# ICPS2023_5_fd_base -- LEF macro views (generated from the GDS)
# Layer names follow the PDK design layers (see libs.tech/klayout/doc/layers.md).
# Geometry is metal-only pad ring hardware; no LEF tech file is shipped yet
# (that arrives with the LibreLane/OpenROAD bring-up).
VERSION 5.7 ;
BUSBITCHARS "[]" ;
DIVIDERCHAR "/" ;
UNITS
  DATABASE MICRONS 1000 ;   # PDK database unit is 0.001 um
END UNITS
MANUFACTURINGGRID 0.001 ;

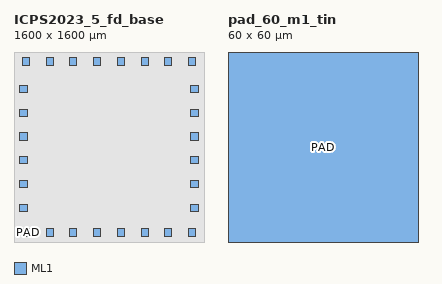
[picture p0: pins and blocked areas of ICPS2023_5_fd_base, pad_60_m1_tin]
MACRO ICPS2023_5_fd_base
  CLASS BLOCK ;
  ORIGIN 0 0 ;
  FOREIGN ICPS2023_5_fd_base 0 0 ;
  SIZE 1600.0 BY 1600.0 ;
  SYMMETRY X Y ;
  PIN PAD
    DIRECTION INOUT ;
    USE ANALOG ;
    PORT
      LAYER ML1 ;
      RECT 70.0 50.0 130.0 110.0 ;
      RECT 270.0 50.0 330.0 110.0 ;
      RECT 470.0 50.0 530.0 110.0 ;
      RECT 670.0 50.0 730.0 110.0 ;
      RECT 870.0 50.0 930.0 110.0 ;
      RECT 1070.0 50.0 1130.0 110.0 ;
      RECT 1270.0 50.0 1330.0 110.0 ;
      RECT 1470.0 50.0 1530.0 110.0 ;
      RECT 50.0 258.0 110.0 318.0 ;
      RECT 1490.0 258.0 1550.0 318.0 ;
      RECT 50.0 458.0 110.0 518.0 ;
      RECT 1490.0 458.0 1550.0 518.0 ;
      RECT 50.0 658.0 110.0 718.0 ;
      RECT 1490.0 658.0 1550.0 718.0 ;
      RECT 50.0 858.0 110.0 918.0 ;
      RECT 1490.0 858.0 1550.0 918.0 ;
      RECT 50.0 1058.0 110.0 1118.0 ;
      RECT 1490.0 1058.0 1550.0 1118.0 ;
      RECT 50.0 1258.0 110.0 1318.0 ;
      RECT 1490.0 1258.0 1550.0 1318.0 ;
      RECT 70.0 1490.0 130.0 1550.0 ;
      RECT 270.0 1490.0 330.0 1550.0 ;
      RECT 470.0 1490.0 530.0 1550.0 ;
      RECT 670.0 1490.0 730.0 1550.0 ;
      RECT 870.0 1490.0 930.0 1550.0 ;
      RECT 1070.0 1490.0 1130.0 1550.0 ;
      RECT 1270.0 1490.0 1330.0 1550.0 ;
      RECT 1470.0 1490.0 1530.0 1550.0 ;
    END
  END PAD
  OBS
    LAYER CNT ;
      RECT 1495.0 1264.0 1500.0 1269.0 ;
      RECT 1510.0 1264.0 1515.0 1269.0 ;
      RECT 1525.0 1264.0 1530.0 1269.0 ;
      RECT 1540.0 1264.0 1545.0 1269.0 ;
      RECT 1495.0 1279.0 1500.0 1284.0 ;
      RECT 1510.0 1279.0 1515.0 1284.0 ;
      RECT 1525.0 1279.0 1530.0 1284.0 ;
      RECT 1540.0 1279.0 1545.0 1284.0 ;
      RECT 1495.0 1294.0 1500.0 1299.0 ;
      RECT 1510.0 1294.0 1515.0 1299.0 ;
      RECT 1525.0 1294.0 1530.0 1299.0 ;
      RECT 1540.0 1294.0 1545.0 1299.0 ;
      RECT 1495.0 1309.0 1500.0 1314.0 ;
      RECT 1510.0 1309.0 1515.0 1314.0 ;
      RECT 1525.0 1309.0 1530.0 1314.0 ;
      RECT 1540.0 1309.0 1545.0 1314.0 ;
      RECT 1276.0 1495.0 1281.0 1500.0 ;
      RECT 1291.0 1495.0 1296.0 1500.0 ;
      RECT 1306.0 1495.0 1311.0 1500.0 ;
      RECT 1321.0 1495.0 1326.0 1500.0 ;
      RECT 1476.0 1495.0 1481.0 1500.0 ;
      RECT 1491.0 1495.0 1496.0 1500.0 ;
      RECT 1506.0 1495.0 1511.0 1500.0 ;
      RECT 1521.0 1495.0 1526.0 1500.0 ;
      RECT 1276.0 1510.0 1281.0 1515.0 ;
      RECT 1291.0 1510.0 1296.0 1515.0 ;
      RECT 1306.0 1510.0 1311.0 1515.0 ;
      RECT 1321.0 1510.0 1326.0 1515.0 ;
      RECT 1476.0 1510.0 1481.0 1515.0 ;
      RECT 1491.0 1510.0 1496.0 1515.0 ;
      RECT 1506.0 1510.0 1511.0 1515.0 ;
      RECT 1521.0 1510.0 1526.0 1515.0 ;
      RECT 1276.0 1525.0 1281.0 1530.0 ;
      RECT 1291.0 1525.0 1296.0 1530.0 ;
      RECT 1306.0 1525.0 1311.0 1530.0 ;
      RECT 1321.0 1525.0 1326.0 1530.0 ;
      RECT 1476.0 1525.0 1481.0 1530.0 ;
      RECT 1491.0 1525.0 1496.0 1530.0 ;
      RECT 1506.0 1525.0 1511.0 1530.0 ;
      RECT 1521.0 1525.0 1526.0 1530.0 ;
      RECT 1276.0 1540.0 1281.0 1545.0 ;
      RECT 1291.0 1540.0 1296.0 1545.0 ;
      RECT 1306.0 1540.0 1311.0 1545.0 ;
      RECT 1321.0 1540.0 1326.0 1545.0 ;
      RECT 1476.0 1540.0 1481.0 1545.0 ;
      RECT 1491.0 1540.0 1496.0 1545.0 ;
      RECT 1506.0 1540.0 1511.0 1545.0 ;
      RECT 1521.0 1540.0 1526.0 1545.0 ;
      RECT 876.0 1525.0 881.0 1530.0 ;
      RECT 891.0 1525.0 896.0 1530.0 ;
      RECT 906.0 1525.0 911.0 1530.0 ;
      RECT 921.0 1525.0 926.0 1530.0 ;
      RECT 1076.0 1525.0 1081.0 1530.0 ;
      RECT 1091.0 1525.0 1096.0 1530.0 ;
      RECT 1106.0 1525.0 1111.0 1530.0 ;
      RECT 1121.0 1525.0 1126.0 1530.0 ;
      RECT 876.0 1510.0 881.0 1515.0 ;
      RECT 891.0 1510.0 896.0 1515.0 ;
      RECT 906.0 1510.0 911.0 1515.0 ;
      RECT 921.0 1510.0 926.0 1515.0 ;
      RECT 1076.0 1510.0 1081.0 1515.0 ;
      RECT 1091.0 1510.0 1096.0 1515.0 ;
      RECT 1106.0 1510.0 1111.0 1515.0 ;
      RECT 1121.0 1510.0 1126.0 1515.0 ;
      RECT 876.0 1540.0 881.0 1545.0 ;
      RECT 891.0 1540.0 896.0 1545.0 ;
      RECT 906.0 1540.0 911.0 1545.0 ;
      RECT 921.0 1540.0 926.0 1545.0 ;
      RECT 1076.0 1540.0 1081.0 1545.0 ;
      RECT 1091.0 1540.0 1096.0 1545.0 ;
      RECT 1106.0 1540.0 1111.0 1545.0 ;
      RECT 1121.0 1540.0 1126.0 1545.0 ;
      RECT 876.0 1495.0 881.0 1500.0 ;
      RECT 891.0 1495.0 896.0 1500.0 ;
      RECT 906.0 1495.0 911.0 1500.0 ;
      RECT 921.0 1495.0 926.0 1500.0 ;
      RECT 1076.0 1495.0 1081.0 1500.0 ;
      RECT 1091.0 1495.0 1096.0 1500.0 ;
      RECT 1106.0 1495.0 1111.0 1500.0 ;
      RECT 1121.0 1495.0 1126.0 1500.0 ;
      RECT 1495.0 1064.0 1500.0 1069.0 ;
      RECT 1510.0 1064.0 1515.0 1069.0 ;
      RECT 1525.0 1064.0 1530.0 1069.0 ;
      RECT 1540.0 1064.0 1545.0 1069.0 ;
      RECT 1495.0 1079.0 1500.0 1084.0 ;
      RECT 1510.0 1079.0 1515.0 1084.0 ;
      RECT 1525.0 1079.0 1530.0 1084.0 ;
      RECT 1540.0 1079.0 1545.0 1084.0 ;
      RECT 1495.0 1094.0 1500.0 1099.0 ;
      RECT 1510.0 1094.0 1515.0 1099.0 ;
      RECT 1525.0 1094.0 1530.0 1099.0 ;
      RECT 1540.0 1094.0 1545.0 1099.0 ;
      RECT 1495.0 1109.0 1500.0 1114.0 ;
      RECT 1510.0 1109.0 1515.0 1114.0 ;
      RECT 1525.0 1109.0 1530.0 1114.0 ;
      RECT 1540.0 1109.0 1545.0 1114.0 ;
      RECT 1495.0 864.0 1500.0 869.0 ;
      RECT 1510.0 864.0 1515.0 869.0 ;
      RECT 1525.0 864.0 1530.0 869.0 ;
      RECT 1540.0 864.0 1545.0 869.0 ;
      RECT 1495.0 879.0 1500.0 884.0 ;
      RECT 1510.0 879.0 1515.0 884.0 ;
      RECT 1525.0 879.0 1530.0 884.0 ;
      RECT 1540.0 879.0 1545.0 884.0 ;
      RECT 1495.0 894.0 1500.0 899.0 ;
      RECT 1510.0 894.0 1515.0 899.0 ;
      RECT 1525.0 894.0 1530.0 899.0 ;
      RECT 1540.0 894.0 1545.0 899.0 ;
      RECT 1495.0 909.0 1500.0 914.0 ;
      RECT 1510.0 909.0 1515.0 914.0 ;
      RECT 1525.0 909.0 1530.0 914.0 ;
      RECT 1540.0 909.0 1545.0 914.0 ;
      RECT 476.0 1510.0 481.0 1515.0 ;
      RECT 491.0 1510.0 496.0 1515.0 ;
      RECT 506.0 1510.0 511.0 1515.0 ;
      RECT 521.0 1510.0 526.0 1515.0 ;
      RECT 676.0 1510.0 681.0 1515.0 ;
      RECT 691.0 1510.0 696.0 1515.0 ;
      RECT 706.0 1510.0 711.0 1515.0 ;
      RECT 721.0 1510.0 726.0 1515.0 ;
      RECT 476.0 1525.0 481.0 1530.0 ;
      RECT 491.0 1525.0 496.0 1530.0 ;
      RECT 506.0 1525.0 511.0 1530.0 ;
      RECT 521.0 1525.0 526.0 1530.0 ;
      RECT 676.0 1525.0 681.0 1530.0 ;
      RECT 691.0 1525.0 696.0 1530.0 ;
      RECT 706.0 1525.0 711.0 1530.0 ;
      RECT 721.0 1525.0 726.0 1530.0 ;
      RECT 476.0 1540.0 481.0 1545.0 ;
      RECT 491.0 1540.0 496.0 1545.0 ;
      RECT 506.0 1540.0 511.0 1545.0 ;
      RECT 521.0 1540.0 526.0 1545.0 ;
      RECT 676.0 1540.0 681.0 1545.0 ;
      RECT 691.0 1540.0 696.0 1545.0 ;
      RECT 706.0 1540.0 711.0 1545.0 ;
      RECT 721.0 1540.0 726.0 1545.0 ;
      RECT 476.0 1495.0 481.0 1500.0 ;
      RECT 491.0 1495.0 496.0 1500.0 ;
      RECT 506.0 1495.0 511.0 1500.0 ;
      RECT 521.0 1495.0 526.0 1500.0 ;
      RECT 676.0 1495.0 681.0 1500.0 ;
      RECT 691.0 1495.0 696.0 1500.0 ;
      RECT 706.0 1495.0 711.0 1500.0 ;
      RECT 721.0 1495.0 726.0 1500.0 ;
      RECT 76.0 1510.0 81.0 1515.0 ;
      RECT 91.0 1510.0 96.0 1515.0 ;
      RECT 106.0 1510.0 111.0 1515.0 ;
      RECT 121.0 1510.0 126.0 1515.0 ;
      RECT 276.0 1510.0 281.0 1515.0 ;
      RECT 291.0 1510.0 296.0 1515.0 ;
      RECT 306.0 1510.0 311.0 1515.0 ;
      RECT 321.0 1510.0 326.0 1515.0 ;
      RECT 55.0 1294.0 60.0 1299.0 ;
      RECT 70.0 1294.0 75.0 1299.0 ;
      RECT 85.0 1294.0 90.0 1299.0 ;
      RECT 100.0 1294.0 105.0 1299.0 ;
      RECT 55.0 1309.0 60.0 1314.0 ;
      RECT 70.0 1309.0 75.0 1314.0 ;
      RECT 85.0 1309.0 90.0 1314.0 ;
      RECT 100.0 1309.0 105.0 1314.0 ;
      RECT 76.0 1540.0 81.0 1545.0 ;
      RECT 91.0 1540.0 96.0 1545.0 ;
      RECT 106.0 1540.0 111.0 1545.0 ;
      RECT 121.0 1540.0 126.0 1545.0 ;
      RECT 276.0 1540.0 281.0 1545.0 ;
      RECT 291.0 1540.0 296.0 1545.0 ;
      RECT 306.0 1540.0 311.0 1545.0 ;
      RECT 321.0 1540.0 326.0 1545.0 ;
      RECT 55.0 1264.0 60.0 1269.0 ;
      RECT 70.0 1264.0 75.0 1269.0 ;
      RECT 85.0 1264.0 90.0 1269.0 ;
      RECT 100.0 1264.0 105.0 1269.0 ;
      RECT 55.0 1279.0 60.0 1284.0 ;
      RECT 70.0 1279.0 75.0 1284.0 ;
      RECT 85.0 1279.0 90.0 1284.0 ;
      RECT 100.0 1279.0 105.0 1284.0 ;
      RECT 76.0 1495.0 81.0 1500.0 ;
      RECT 91.0 1495.0 96.0 1500.0 ;
      RECT 106.0 1495.0 111.0 1500.0 ;
      RECT 121.0 1495.0 126.0 1500.0 ;
      RECT 276.0 1495.0 281.0 1500.0 ;
      RECT 291.0 1495.0 296.0 1500.0 ;
      RECT 306.0 1495.0 311.0 1500.0 ;
      RECT 321.0 1495.0 326.0 1500.0 ;
      RECT 76.0 1525.0 81.0 1530.0 ;
      RECT 91.0 1525.0 96.0 1530.0 ;
      RECT 106.0 1525.0 111.0 1530.0 ;
      RECT 121.0 1525.0 126.0 1530.0 ;
      RECT 276.0 1525.0 281.0 1530.0 ;
      RECT 291.0 1525.0 296.0 1530.0 ;
      RECT 306.0 1525.0 311.0 1530.0 ;
      RECT 321.0 1525.0 326.0 1530.0 ;
      RECT 55.0 1109.0 60.0 1114.0 ;
      RECT 70.0 1109.0 75.0 1114.0 ;
      RECT 85.0 1109.0 90.0 1114.0 ;
      RECT 100.0 1109.0 105.0 1114.0 ;
      RECT 55.0 864.0 60.0 869.0 ;
      RECT 70.0 864.0 75.0 869.0 ;
      RECT 85.0 864.0 90.0 869.0 ;
      RECT 100.0 864.0 105.0 869.0 ;
      RECT 55.0 1094.0 60.0 1099.0 ;
      RECT 70.0 1094.0 75.0 1099.0 ;
      RECT 85.0 1094.0 90.0 1099.0 ;
      RECT 100.0 1094.0 105.0 1099.0 ;
      RECT 55.0 1064.0 60.0 1069.0 ;
      RECT 70.0 1064.0 75.0 1069.0 ;
      RECT 85.0 1064.0 90.0 1069.0 ;
      RECT 100.0 1064.0 105.0 1069.0 ;
      RECT 55.0 909.0 60.0 914.0 ;
      RECT 70.0 909.0 75.0 914.0 ;
      RECT 85.0 909.0 90.0 914.0 ;
      RECT 100.0 909.0 105.0 914.0 ;
      RECT 55.0 1079.0 60.0 1084.0 ;
      RECT 70.0 1079.0 75.0 1084.0 ;
      RECT 85.0 1079.0 90.0 1084.0 ;
      RECT 100.0 1079.0 105.0 1084.0 ;
      RECT 55.0 894.0 60.0 899.0 ;
      RECT 70.0 894.0 75.0 899.0 ;
      RECT 85.0 894.0 90.0 899.0 ;
      RECT 100.0 894.0 105.0 899.0 ;
      RECT 55.0 879.0 60.0 884.0 ;
      RECT 70.0 879.0 75.0 884.0 ;
      RECT 85.0 879.0 90.0 884.0 ;
      RECT 100.0 879.0 105.0 884.0 ;
      RECT 55.0 464.0 60.0 469.0 ;
      RECT 70.0 464.0 75.0 469.0 ;
      RECT 85.0 464.0 90.0 469.0 ;
      RECT 100.0 464.0 105.0 469.0 ;
      RECT 55.0 479.0 60.0 484.0 ;
      RECT 70.0 479.0 75.0 484.0 ;
      RECT 85.0 479.0 90.0 484.0 ;
      RECT 100.0 479.0 105.0 484.0 ;
      RECT 55.0 494.0 60.0 499.0 ;
      RECT 70.0 494.0 75.0 499.0 ;
      RECT 85.0 494.0 90.0 499.0 ;
      RECT 100.0 494.0 105.0 499.0 ;
      RECT 55.0 509.0 60.0 514.0 ;
      RECT 70.0 509.0 75.0 514.0 ;
      RECT 85.0 509.0 90.0 514.0 ;
      RECT 100.0 509.0 105.0 514.0 ;
      RECT 55.0 664.0 60.0 669.0 ;
      RECT 70.0 664.0 75.0 669.0 ;
      RECT 85.0 664.0 90.0 669.0 ;
      RECT 100.0 664.0 105.0 669.0 ;
      RECT 55.0 679.0 60.0 684.0 ;
      RECT 70.0 679.0 75.0 684.0 ;
      RECT 85.0 679.0 90.0 684.0 ;
      RECT 100.0 679.0 105.0 684.0 ;
      RECT 55.0 694.0 60.0 699.0 ;
      RECT 70.0 694.0 75.0 699.0 ;
      RECT 85.0 694.0 90.0 699.0 ;
      RECT 100.0 694.0 105.0 699.0 ;
      RECT 55.0 709.0 60.0 714.0 ;
      RECT 70.0 709.0 75.0 714.0 ;
      RECT 85.0 709.0 90.0 714.0 ;
      RECT 100.0 709.0 105.0 714.0 ;
      RECT 55.0 264.0 60.0 269.0 ;
      RECT 70.0 264.0 75.0 269.0 ;
      RECT 85.0 264.0 90.0 269.0 ;
      RECT 100.0 264.0 105.0 269.0 ;
      RECT 55.0 279.0 60.0 284.0 ;
      RECT 70.0 279.0 75.0 284.0 ;
      RECT 85.0 279.0 90.0 284.0 ;
      RECT 100.0 279.0 105.0 284.0 ;
      RECT 55.0 294.0 60.0 299.0 ;
      RECT 70.0 294.0 75.0 299.0 ;
      RECT 85.0 294.0 90.0 299.0 ;
      RECT 100.0 294.0 105.0 299.0 ;
      RECT 55.0 309.0 60.0 314.0 ;
      RECT 70.0 309.0 75.0 314.0 ;
      RECT 85.0 309.0 90.0 314.0 ;
      RECT 100.0 309.0 105.0 314.0 ;
      RECT 76.0 55.0 81.0 60.0 ;
      RECT 91.0 55.0 96.0 60.0 ;
      RECT 106.0 55.0 111.0 60.0 ;
      RECT 121.0 55.0 126.0 60.0 ;
      RECT 276.0 55.0 281.0 60.0 ;
      RECT 291.0 55.0 296.0 60.0 ;
      RECT 306.0 55.0 311.0 60.0 ;
      RECT 321.0 55.0 326.0 60.0 ;
      RECT 76.0 70.0 81.0 75.0 ;
      RECT 91.0 70.0 96.0 75.0 ;
      RECT 106.0 70.0 111.0 75.0 ;
      RECT 121.0 70.0 126.0 75.0 ;
      RECT 276.0 70.0 281.0 75.0 ;
      RECT 291.0 70.0 296.0 75.0 ;
      RECT 306.0 70.0 311.0 75.0 ;
      RECT 321.0 70.0 326.0 75.0 ;
      RECT 76.0 85.0 81.0 90.0 ;
      RECT 91.0 85.0 96.0 90.0 ;
      RECT 106.0 85.0 111.0 90.0 ;
      RECT 121.0 85.0 126.0 90.0 ;
      RECT 276.0 85.0 281.0 90.0 ;
      RECT 291.0 85.0 296.0 90.0 ;
      RECT 306.0 85.0 311.0 90.0 ;
      RECT 321.0 85.0 326.0 90.0 ;
      RECT 76.0 100.0 81.0 105.0 ;
      RECT 91.0 100.0 96.0 105.0 ;
      RECT 106.0 100.0 111.0 105.0 ;
      RECT 121.0 100.0 126.0 105.0 ;
      RECT 276.0 100.0 281.0 105.0 ;
      RECT 291.0 100.0 296.0 105.0 ;
      RECT 306.0 100.0 311.0 105.0 ;
      RECT 321.0 100.0 326.0 105.0 ;
      RECT 476.0 70.0 481.0 75.0 ;
      RECT 491.0 70.0 496.0 75.0 ;
      RECT 506.0 70.0 511.0 75.0 ;
      RECT 521.0 70.0 526.0 75.0 ;
      RECT 676.0 70.0 681.0 75.0 ;
      RECT 691.0 70.0 696.0 75.0 ;
      RECT 706.0 70.0 711.0 75.0 ;
      RECT 721.0 70.0 726.0 75.0 ;
      RECT 476.0 100.0 481.0 105.0 ;
      RECT 491.0 100.0 496.0 105.0 ;
      RECT 506.0 100.0 511.0 105.0 ;
      RECT 521.0 100.0 526.0 105.0 ;
      RECT 676.0 100.0 681.0 105.0 ;
      RECT 691.0 100.0 696.0 105.0 ;
      RECT 706.0 100.0 711.0 105.0 ;
      RECT 721.0 100.0 726.0 105.0 ;
      RECT 476.0 55.0 481.0 60.0 ;
      RECT 491.0 55.0 496.0 60.0 ;
      RECT 506.0 55.0 511.0 60.0 ;
      RECT 521.0 55.0 526.0 60.0 ;
      RECT 676.0 55.0 681.0 60.0 ;
      RECT 691.0 55.0 696.0 60.0 ;
      RECT 706.0 55.0 711.0 60.0 ;
      RECT 721.0 55.0 726.0 60.0 ;
      RECT 476.0 85.0 481.0 90.0 ;
      RECT 491.0 85.0 496.0 90.0 ;
      RECT 506.0 85.0 511.0 90.0 ;
      RECT 521.0 85.0 526.0 90.0 ;
      RECT 676.0 85.0 681.0 90.0 ;
      RECT 691.0 85.0 696.0 90.0 ;
      RECT 706.0 85.0 711.0 90.0 ;
      RECT 721.0 85.0 726.0 90.0 ;
      RECT 1495.0 464.0 1500.0 469.0 ;
      RECT 1510.0 464.0 1515.0 469.0 ;
      RECT 1525.0 464.0 1530.0 469.0 ;
      RECT 1540.0 464.0 1545.0 469.0 ;
      RECT 1495.0 479.0 1500.0 484.0 ;
      RECT 1510.0 479.0 1515.0 484.0 ;
      RECT 1525.0 479.0 1530.0 484.0 ;
      RECT 1540.0 479.0 1545.0 484.0 ;
      RECT 1495.0 494.0 1500.0 499.0 ;
      RECT 1510.0 494.0 1515.0 499.0 ;
      RECT 1525.0 494.0 1530.0 499.0 ;
      RECT 1540.0 494.0 1545.0 499.0 ;
      RECT 1495.0 509.0 1500.0 514.0 ;
      RECT 1510.0 509.0 1515.0 514.0 ;
      RECT 1525.0 509.0 1530.0 514.0 ;
      RECT 1540.0 509.0 1545.0 514.0 ;
      RECT 1495.0 664.0 1500.0 669.0 ;
      RECT 1510.0 664.0 1515.0 669.0 ;
      RECT 1525.0 664.0 1530.0 669.0 ;
      RECT 1540.0 664.0 1545.0 669.0 ;
      RECT 1495.0 679.0 1500.0 684.0 ;
      RECT 1510.0 679.0 1515.0 684.0 ;
      RECT 1525.0 679.0 1530.0 684.0 ;
      RECT 1540.0 679.0 1545.0 684.0 ;
      RECT 1495.0 694.0 1500.0 699.0 ;
      RECT 1510.0 694.0 1515.0 699.0 ;
      RECT 1525.0 694.0 1530.0 699.0 ;
      RECT 1540.0 694.0 1545.0 699.0 ;
      RECT 1495.0 709.0 1500.0 714.0 ;
      RECT 1510.0 709.0 1515.0 714.0 ;
      RECT 1525.0 709.0 1530.0 714.0 ;
      RECT 1540.0 709.0 1545.0 714.0 ;
      RECT 876.0 55.0 881.0 60.0 ;
      RECT 891.0 55.0 896.0 60.0 ;
      RECT 906.0 55.0 911.0 60.0 ;
      RECT 921.0 55.0 926.0 60.0 ;
      RECT 1076.0 55.0 1081.0 60.0 ;
      RECT 1091.0 55.0 1096.0 60.0 ;
      RECT 1106.0 55.0 1111.0 60.0 ;
      RECT 1121.0 55.0 1126.0 60.0 ;
      RECT 876.0 70.0 881.0 75.0 ;
      RECT 891.0 70.0 896.0 75.0 ;
      RECT 906.0 70.0 911.0 75.0 ;
      RECT 921.0 70.0 926.0 75.0 ;
      RECT 876.0 85.0 881.0 90.0 ;
      RECT 891.0 85.0 896.0 90.0 ;
      RECT 906.0 85.0 911.0 90.0 ;
      RECT 921.0 85.0 926.0 90.0 ;
      RECT 1076.0 70.0 1081.0 75.0 ;
      RECT 1091.0 70.0 1096.0 75.0 ;
      RECT 1106.0 70.0 1111.0 75.0 ;
      RECT 1121.0 70.0 1126.0 75.0 ;
      RECT 876.0 100.0 881.0 105.0 ;
      RECT 891.0 100.0 896.0 105.0 ;
      RECT 906.0 100.0 911.0 105.0 ;
      RECT 921.0 100.0 926.0 105.0 ;
      RECT 1076.0 85.0 1081.0 90.0 ;
      RECT 1091.0 85.0 1096.0 90.0 ;
      RECT 1106.0 85.0 1111.0 90.0 ;
      RECT 1121.0 85.0 1126.0 90.0 ;
      RECT 1076.0 100.0 1081.0 105.0 ;
      RECT 1091.0 100.0 1096.0 105.0 ;
      RECT 1106.0 100.0 1111.0 105.0 ;
      RECT 1121.0 100.0 1126.0 105.0 ;
      RECT 1276.0 85.0 1281.0 90.0 ;
      RECT 1291.0 85.0 1296.0 90.0 ;
      RECT 1306.0 85.0 1311.0 90.0 ;
      RECT 1321.0 85.0 1326.0 90.0 ;
      RECT 1276.0 55.0 1281.0 60.0 ;
      RECT 1291.0 55.0 1296.0 60.0 ;
      RECT 1306.0 55.0 1311.0 60.0 ;
      RECT 1321.0 55.0 1326.0 60.0 ;
      RECT 1476.0 85.0 1481.0 90.0 ;
      RECT 1491.0 85.0 1496.0 90.0 ;
      RECT 1506.0 85.0 1511.0 90.0 ;
      RECT 1521.0 85.0 1526.0 90.0 ;
      RECT 1495.0 294.0 1500.0 299.0 ;
      RECT 1510.0 294.0 1515.0 299.0 ;
      RECT 1525.0 294.0 1530.0 299.0 ;
      RECT 1540.0 294.0 1545.0 299.0 ;
      RECT 1476.0 55.0 1481.0 60.0 ;
      RECT 1491.0 55.0 1496.0 60.0 ;
      RECT 1506.0 55.0 1511.0 60.0 ;
      RECT 1521.0 55.0 1526.0 60.0 ;
      RECT 1495.0 309.0 1500.0 314.0 ;
      RECT 1510.0 309.0 1515.0 314.0 ;
      RECT 1525.0 309.0 1530.0 314.0 ;
      RECT 1540.0 309.0 1545.0 314.0 ;
      RECT 1276.0 100.0 1281.0 105.0 ;
      RECT 1291.0 100.0 1296.0 105.0 ;
      RECT 1306.0 100.0 1311.0 105.0 ;
      RECT 1321.0 100.0 1326.0 105.0 ;
      RECT 1495.0 264.0 1500.0 269.0 ;
      RECT 1510.0 264.0 1515.0 269.0 ;
      RECT 1525.0 264.0 1530.0 269.0 ;
      RECT 1540.0 264.0 1545.0 269.0 ;
      RECT 1276.0 70.0 1281.0 75.0 ;
      RECT 1291.0 70.0 1296.0 75.0 ;
      RECT 1306.0 70.0 1311.0 75.0 ;
      RECT 1321.0 70.0 1326.0 75.0 ;
      RECT 1476.0 100.0 1481.0 105.0 ;
      RECT 1491.0 100.0 1496.0 105.0 ;
      RECT 1506.0 100.0 1511.0 105.0 ;
      RECT 1521.0 100.0 1526.0 105.0 ;
      RECT 1476.0 70.0 1481.0 75.0 ;
      RECT 1491.0 70.0 1496.0 75.0 ;
      RECT 1506.0 70.0 1511.0 75.0 ;
      RECT 1521.0 70.0 1526.0 75.0 ;
      RECT 1495.0 279.0 1500.0 284.0 ;
      RECT 1510.0 279.0 1515.0 284.0 ;
      RECT 1525.0 279.0 1530.0 284.0 ;
      RECT 1540.0 279.0 1545.0 284.0 ;
    LAYER FRAME ;
      RECT 0.0 0.0 1600.0 1600.0 ;
    LAYER TIN ;
      RECT 70.0 50.0 130.0 110.0 ;
      RECT 270.0 50.0 330.0 110.0 ;
      RECT 470.0 50.0 530.0 110.0 ;
      RECT 670.0 50.0 730.0 110.0 ;
      RECT 870.0 50.0 930.0 110.0 ;
      RECT 1070.0 50.0 1130.0 110.0 ;
      RECT 1270.0 50.0 1330.0 110.0 ;
      RECT 1470.0 50.0 1530.0 110.0 ;
      RECT 50.0 258.0 110.0 318.0 ;
      RECT 1490.0 258.0 1550.0 318.0 ;
      RECT 50.0 458.0 110.0 518.0 ;
      RECT 1490.0 458.0 1550.0 518.0 ;
      RECT 50.0 658.0 110.0 718.0 ;
      RECT 1490.0 658.0 1550.0 718.0 ;
      RECT 50.0 858.0 110.0 918.0 ;
      RECT 1490.0 858.0 1550.0 918.0 ;
      RECT 50.0 1058.0 110.0 1118.0 ;
      RECT 1490.0 1058.0 1550.0 1118.0 ;
      RECT 50.0 1258.0 110.0 1318.0 ;
      RECT 1490.0 1258.0 1550.0 1318.0 ;
      RECT 70.0 1490.0 130.0 1550.0 ;
      RECT 270.0 1490.0 330.0 1550.0 ;
      RECT 470.0 1490.0 530.0 1550.0 ;
      RECT 670.0 1490.0 730.0 1550.0 ;
      RECT 870.0 1490.0 930.0 1550.0 ;
      RECT 1070.0 1490.0 1130.0 1550.0 ;
      RECT 1270.0 1490.0 1330.0 1550.0 ;
      RECT 1470.0 1490.0 1530.0 1550.0 ;
  END
END ICPS2023_5_fd_base

MACRO pad_60_m1_tin
  CLASS PAD ;
  ORIGIN 0 0 ;
  FOREIGN pad_60_m1_tin 0 0 ;
  SIZE 60.0 BY 60.0 ;
  SYMMETRY X Y ;
  PIN PAD
    DIRECTION INOUT ;
    USE ANALOG ;
    PORT
      LAYER ML1 ;
      RECT 0.0 0.0 60.0 60.0 ;
    END
  END PAD
  OBS
    LAYER CNT ;
      RECT 5.0 4.0 10.0 9.0 ;
      RECT 20.0 4.0 25.0 9.0 ;
      RECT 35.0 4.0 40.0 9.0 ;
      RECT 50.0 4.0 55.0 9.0 ;
      RECT 5.0 19.0 10.0 24.0 ;
      RECT 20.0 19.0 25.0 24.0 ;
      RECT 35.0 19.0 40.0 24.0 ;
      RECT 50.0 19.0 55.0 24.0 ;
      RECT 5.0 34.0 10.0 39.0 ;
      RECT 20.0 34.0 25.0 39.0 ;
      RECT 35.0 34.0 40.0 39.0 ;
      RECT 50.0 34.0 55.0 39.0 ;
      RECT 5.0 49.0 10.0 54.0 ;
      RECT 20.0 49.0 25.0 54.0 ;
      RECT 35.0 49.0 40.0 54.0 ;
      RECT 50.0 49.0 55.0 54.0 ;
    LAYER TIN ;
      RECT 0.0 0.0 60.0 60.0 ;
  END
END pad_60_m1_tin
